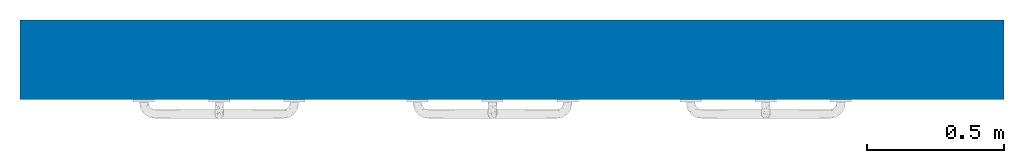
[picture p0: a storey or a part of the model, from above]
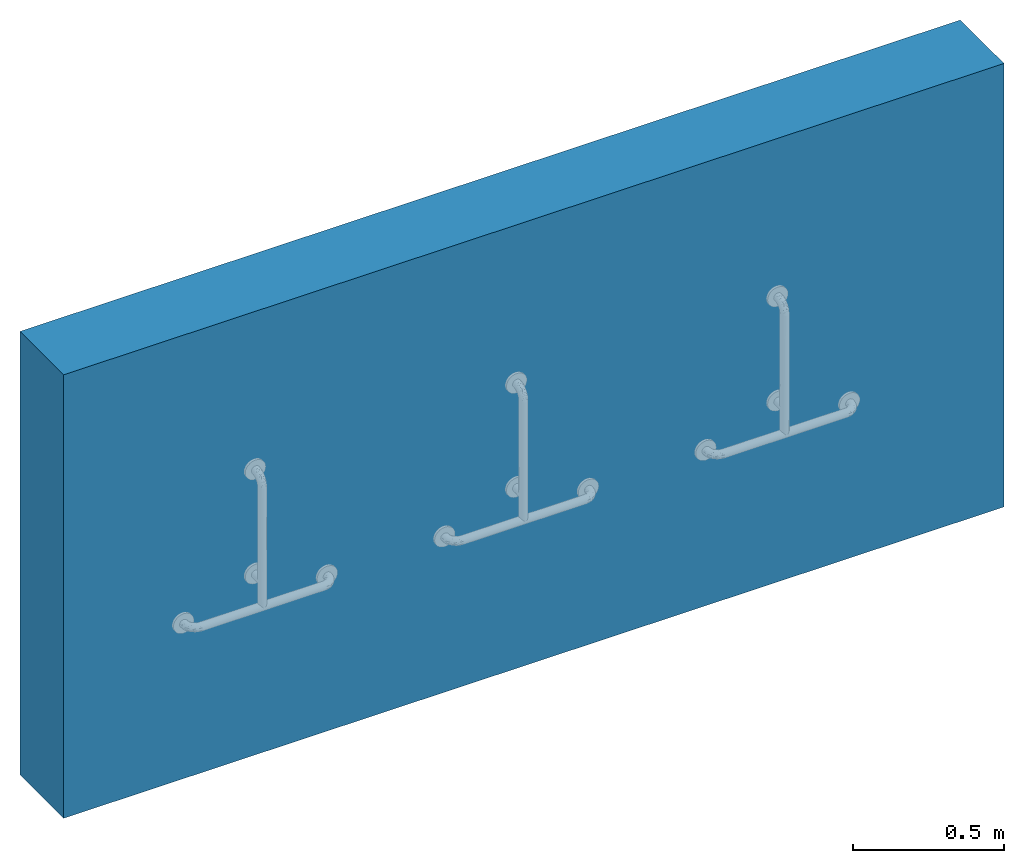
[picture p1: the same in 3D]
Properties of the parts of a building model (IFC2X3)

# File
Description: ViewDefinition [COBie2.4DesignDeliverable]
File name: Project Number
Time: 2021-10-27T12:15:14
Written by: The EXPRESS Data Manager Version 5.02.0100.07 : 28 Aug 2013
Made in: 20190808_0900(x64) - Exporter 19.2.20.24 - Alternate UI 19.2.20.24
Comment: STEP Physical File produced by: The EXPRESS Data Manager Version 5.02.0100.07 : 28 Aug 2013 * Module: EDMstepFileFactory/EDMstandAlone * Creation date: Wed Oct 27 12:15:14 2021 * Host: DESKTOP-KN3O7NT * Database: C:\Users\SARAHS~1\AppData\Local\Temp\{9FDA5211-4FCE-44FE-A7A7-C2E5340F2776}\ifc * Database version: 5507 * Database creation date: Wed Oct 27 12:15:13 2021 * Schema: IFC2X3 * Model: DataRepository.ifc * Model creation date: Wed Oct 27 12:15:13 2021 * Header model: DataRepository.ifc_HeaderModel * Header model creation date: Wed Oct 27 12:15:13 2021 * EDMuser: sdai-user * EDMgroup: sdai-group * License ID and type: 5605 : Permanent license. Expiry date: * EDMstepFileFactory options: 020000

# IfcProject, Project Number
LongName: Project Name; Phase: Project Status

# IfcSite, Default
RefLatitude: 51, 30, 23, 112487; RefLongitude: 0, -7, -37, -956022; RefElevation: 0 mm

# IfcBuilding
Pset_BuildingCommon - NumberOfStoreys: 1

# IfcBuildingStorey, Level 0
LongName: Level 0; Elevation: 0 mm

# IfcBuildingElementProxy: Brushed Stainless Steel T-Bar Handrail, (3)
In: Level 0
Type - Classification: E2020200 Furniture & Accessories (Uniformat); Material: Duten_Metal_BrushedStainlessSteel
Pset_BuildingElementProxyCommon - Reference: n/a
Pset_ManufacturerTypeInformation - ModelReference: Brushed Stainless Steel T-Bar Handrail; Manufacturer: Duten

# IfcBuildingElementProxy: Polished Stainless Steel T-Bar Handrail, (4)
In: Level 0
Type - Classification: E2020200 Furniture & Accessories (Uniformat); Material: Duten_Metal_BrushedStainlessSteel
Pset_BuildingElementProxyCommon - Reference: n/a
Pset_ManufacturerTypeInformation - ModelReference: Polished Stainless Steel T-Bar Handrail; Manufacturer: Duten

# IfcBuildingElementProxy: White Steel T-Bar Handrail, (5)
In: Level 0
Type - Classification: E2020200 Furniture & Accessories (Uniformat); Material: Duten_Metal_BrushedStainlessSteel
Pset_BuildingElementProxyCommon - Reference: n/a
Pset_ManufacturerTypeInformation - ModelReference: White Steel T-Bar Handrail; Manufacturer: Duten

# IfcWallStandardCase: (2)
In: Level 0
Type - PredefinedType: STANDARD; Material: Brick, Common 102.5 mm, Fiberglass Batt 75 mm, Concrete Masonry Units _Low Density 100 mm, Plaster 12.5 mm
BaseQuantities - Height: 1795.16 mm; Length: 3600 mm; Width: 290 mm; GrossFootprintArea: 1.044 m2; GrossSideArea: 6.46258 m2; GrossVolume: 1.87415 m3
Pset_WallCommon - Reference: Wall-Ext_102Bwk-75Ins-100LBlk-12P; LoadBearing: no; ExtendToStructure: no; IsExternal: yes; ThermalTransmittance: 0.235926 kg/K/s3
